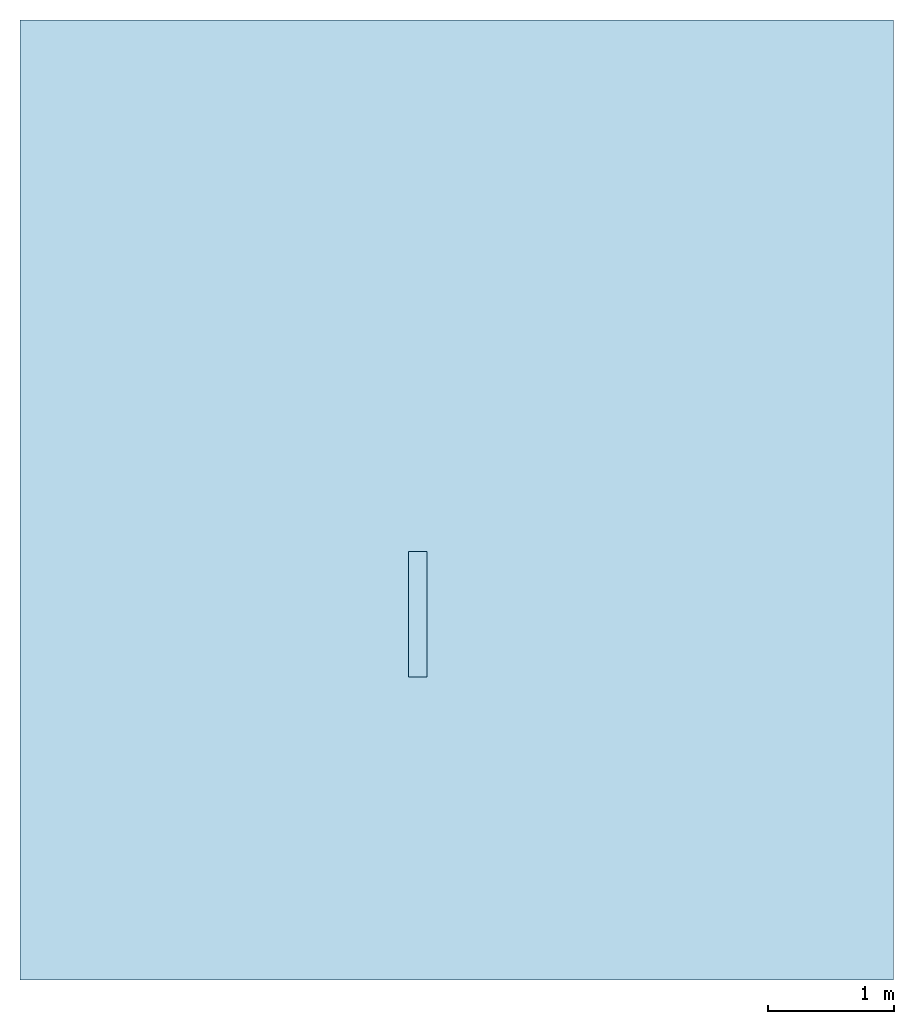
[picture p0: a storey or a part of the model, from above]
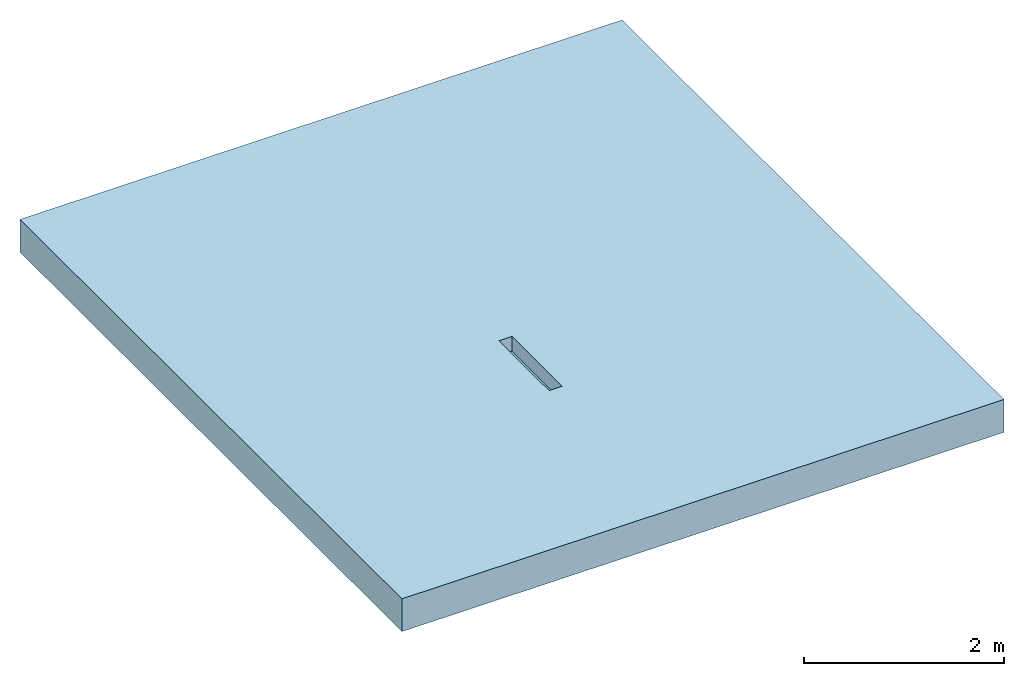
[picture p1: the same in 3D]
Properties of the parts of a building model (IFC2X3)

# File
Description: ViewDefinition [CoordinationView]
File name: 7959 - KDHB305 Channel - 1000mm LG.ifc
Time: 2013-09-12T12:39:50
Written by: Autodesk Revit 2013
Made in: 20120221_2030(x64)

# IfcProject, Project Number
LongName: Project Name; Phase: Project Status

# IfcSite, Default
RefLatitude: 42, 21, 30, 344238; RefLongitude: -71, -3, -35, -194702; RefElevation: 0 mm

# IfcBuilding
Pset_BuildingCommon - NumberOfStoreys: 2
Other - Client Name: Owner; Project Address: Enter address here; Project Name: Project Name; Project Number: Project Number; Project Issue Date: Issue Date; Project Status: Project Status

# IfcBuildingStorey (2)
Constraints - Elevation Base: 0
Graphics - Line Weight: 1; Line Pattern: Center; Symbol at End 1 Default: no; Color: 0; Symbol at End 2 Default: yes; Symbol: M_Level Head - Circle: M_Level Head - Circle
Identity Data - Structural: no; Building Story: yes
Dimensions - Computation Height: 0 mm
Name | LongName = Name | Elevation (mm) = Constraints, Elevation (mm)
T.O. Fnd. Wall | T.O. Fnd. Wall | -300
Level 1 | Level 1 | 0

# IfcBuildingElementProxy: 7959 - KDHB305 Channel - 1000mm LG, Civil-Drainage-Channel-ACO-KerbDrain-HB305 - PART 1:7959 - KDHB305 Channel - 1000mm LG:7959 - KDHB305 Channel - 1000mm LG:255899
In: T.O. Fnd. Wall
Material: ACO Polymer Concrete.
Other - CreatedBy: www.aco.co.uk; Revision: 1
Green Building Properties - Channel Recycled Material Content: 20% minimum; Channel Recyclable: Fully recyclable; End Cap Recyclable: N/A; Access Cover/Frame Recycled Material Content: N/A; Access Cover/Frame Recyclable: N/A; End Cap Recycled Material Content: N/A
Constraints - Level: Level: Level 1; Moves With Nearby Elements: no
Phasing - Phase Created: Phase 1
Dimensions - Volume: 25826904 mm3; Staright Void Depth: -180 mm; Void_Width: 150 mm; I/O Endcap Void depth: 6000 mm; Void_Length: 1000 mm
Pset_BuildingElementProxyCommon - Reference: 7959 - KDHB305 Channel - 1000mm LG
General - TagNumber: 0.000000; SerialNumber: 0.000000
Identity Data - Address: ACO Business Park, Hitchin Road, Shefford, Bedfordshire, United Kingdom SG17 5TE; URL: www.aco.co.uk; Assembly Description: Rain Water Drainage; OmniClass Number: 23.70.50.24; Product brochure: http://www.aco.co.uk/download.php?id=120; E-mail Sales: customersupport@aco.co.uk; Fax: +44 (0)1462 815895; Telephone: +44 (0)1462 816666; Model Description: Combined kerb and drainage system; Product Code: 7959; Product Page URL: http://www.aco.co.uk/product_detail.php?id=3; Model: ACO KerbDrain HB305; Assembly Code: D2040; E-mail Technical: technical@aco.co.uk; Type Comments: ACO KerbDrain HB305 half battered kerb unit 1000mm long; Maintenance guidelines: http://www.aco.co.uk/download.php?id=120; Cost: 0; Price: POA - contact ACO; OmniClass Title: Rainwater Removal; Manufacturer: ACO Technologies plc - ACO Water Management Division; Installation guidelines: http://www.aco.co.uk/download.php?id=120
Construction - KDHB305 - Channel unit - 1000mm: yes; KDHB305 - RH drop kerb: no; KDHB305 - RH Inlet/outlet end cap: no; KDHB305 - Channel unit - 500mm: no; KDHB305 - Closing end cap: no; KDHB305 - Access Unit: no; KDHB305 - Flush LH dropkerb: no; KDHB305 - Drainable centre stone: no; KDHB305 - Flush RH dropkerb: no; KDHB305 - LH Inlet/Outlet end cap: no; I/O Pipe: no; KDHB305 - Perforated centre stone: no; KDHB305 - Blind unit: no; KDHB305 - Centre stone: no; KDHB305 - Channel unit - 250mm: no; KDHB305 - LH drop kerb: no
Materials and Finishes - Access Cover/Frame Finish: N/A; Connection Pipe Material: N/A; Channel Material: Vienite® Synthetic Resin Concrete; End Cap Colour: N/A; End Cap Material: N/A; Access Cover/Frame Colour: N/A; Access Cover/Frame Material: N/A; Connection Pipe Material Colour: N/A; Channel Colour: Grey
Data - Channel C.S.A: 0.02m²; Product Dimensions: 1000mm x 150mm x 305mm (LxWxH); Hydraulic Performance: http://www.aco.co.uk/download.php?id=120; Connection Pipe O.D: N/A; Installation - Concrete Grade: Refer to brochure; Product Weight: 53.1 Kg; ACO Hydraulic Design Software: http://www.acodesign.co.uk; Concrete Surround Volume - Load Class A 15 - D 400 - Concrete Pavement: N/A; Drainage Slot Width: 50mm; Concrete Surround Volume - Load Class A 15 - D 400 - Grass or Asphalt Pavement: N/A; Invert Depth: 280mm; Product Standard: BS EN 1433:2002, CE marked, Kitemarked; Drainage Slot Intake area: 14592mm²/m; Load Class: A 15 - D 400

# IfcOpeningElement: Recess (2)
In: Level 1
Constraints - Room Bounding: yes; Level: Level: Level 1; Height Offset From Level: 0 mm; Related to Mass: no
Dimensions - Perimeter: 29157.2 mm; Area: 53016081 mm2; Volume: 21179432206 mm3; Thickness: 400 mm
Structural - Enable Analytical Model: no; Structural: no
Phasing - Phase Created: Phase 1
Graphics - Coarse Scale Fill Color: 0
Construction - Function: 0; Default Thickness: 400 mm
Analytical Properties - Absorptance: 0.1; Roughness: 1

# IfcSlab: Floor:Generic Floor - 400mm, Floor:Generic Floor - 400mm:184025
In: Level 1
PredefinedType: FLOOR; Material: Default Floor 400 mm
Constraints - Room Bounding: yes; Level: Level: Level 1; Height Offset From Level: 0 mm; Related to Mass: no
Dimensions - Perimeter: 29157.2 mm; Area: 53016081 mm2; Volume: 21179432206 mm3; Thickness: 400 mm
Structural - Enable Analytical Model: no; Structural: no
Phasing - Phase Created: Phase 1
Pset_SlabCommon - Reference: Generic Floor - 400mm; IsExternal: no; LoadBearing: yes
Graphics - Coarse Scale Fill Color: 0
Construction - Function: 0; Default Thickness: 400 mm
Analytical Properties - Absorptance: 0.1; Roughness: 1
